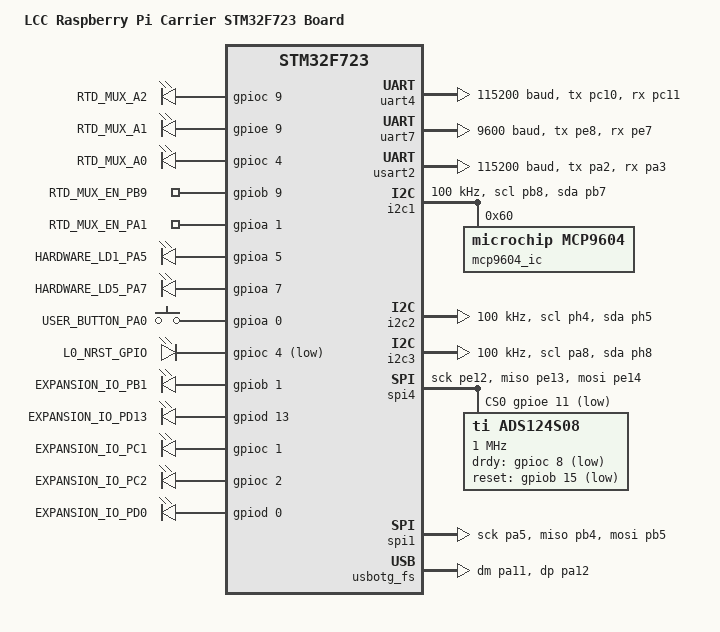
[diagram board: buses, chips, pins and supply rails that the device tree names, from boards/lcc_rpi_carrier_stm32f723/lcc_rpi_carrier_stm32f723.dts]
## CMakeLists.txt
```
cmake_minimum_required(VERSION 3.20.0)
set(BOARD_ROOT ${CMAKE_CURRENT_SOURCE_DIR})
find_package(Zephyr REQUIRED HINTS $ENV{ZEPHYR_BASE})
project(stm32f723_app)

# ==========================================
# Force CMake Re-run
# ==========================================
# 1. Automate .c files (Sources)
# ==========================================
file(GLOB_RECURSE APP_SOURCES 
    "src/*.c"
    "drivers/*.c"
)
target_sources(app PRIVATE ${APP_SOURCES})
# ==========================================
# 2. Automate .h files (Include Directories)
# ==========================================
file(GLOB_RECURSE APP_HEADERS 
    "src/*.h"
    "drivers/*.h"
)
# Extract just the folder path from each header file
set(APP_INCLUDE_DIRS "")
foreach(HEADER_FILE ${APP_HEADERS})
    get_filename_component(HEADER_DIR ${HEADER_FILE} DIRECTORY)
    list(APPEND APP_INCLUDE_DIRS ${HEADER_DIR})
endforeach()
# Remove duplicate folders from the list
list(REMOVE_DUPLICATES APP_INCLUDE_DIRS)
# Give the list of folders to the compiler
target_include_directories(app PRIVATE ${APP_INCLUDE_DIRS})

target_include_directories(app PRIVATE ${ZEPHYR_BASE}/drivers/adc)
```

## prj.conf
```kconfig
# ==========================================
# Core Kernel & System Configuration
# ==========================================
CONFIG_NEWLIB_LIBC=y
CONFIG_HEAP_MEM_POOL_SIZE=2048
CONFIG_CBPRINTF_FP_SUPPORT=y

# ==========================================
# Hardware Busses (I2C, SPI, GPIO)
# ==========================================
CONFIG_GPIO=y
CONFIG_I2C=y
CONFIG_I2C_STM32=y
CONFIG_SPI=y

# ==========================================
# Drivers (Sensors & ADCs)
# ==========================================
CONFIG_SENSOR=y
CONFIG_MCP9600=y
CONFIG_ADC=y
CONFIG_ADC_INIT_PRIORITY=80

# Keep upstream driver disabled, custom driver available
CONFIG_ADC_ADS1X4S0X=n
# Re-enable the structure fields needed by ADS124S08:
# CONFIG_ADC_CONFIGURABLE_INPUTS=y
# CONFIG_ADC_CONFIGURABLE_EXCITATION_CURRENT_SOURCE_PIN=y
# CONFIG_ADC_CONFIGURABLE_VBIAS_PIN=y

# ==========================================
# DMA & UART (Display Protocol)
# ==========================================
CONFIG_SERIAL=y
CONFIG_UART_ASYNC_API=y
CONFIG_DMA=y
CONFIG_NOCACHE_MEMORY=y

# Disable standard UART features to prevent conflicts with DMA
CONFIG_UART_CONSOLE=n
CONFIG_UART_INTERRUPT_DRIVEN=n

# Optional DMA debug
CONFIG_DMA_LOG_LEVEL_DBG=y

# ==========================================
# Logging & Console (SEGGER RTT)
# ==========================================
CONFIG_LOG=y
CONFIG_PRINTK=y
CONFIG_LOG_DEFAULT_LEVEL=3
CONFIG_LOG_RUNTIME_FILTERING=y
CONFIG_ASSERT=y

# Use RTT instead of UART for logs
CONFIG_USE_SEGGER_RTT=y
CONFIG_LOG_BACKEND_RTT=y
CONFIG_RTT_CONSOLE=y
CONFIG_LOG_BACKEND_UART=n
CONFIG_CONSOLE=n
CONFIG_STDOUT_CONSOLE=n

# RTT Buffers & Threading safety
CONFIG_SEGGER_RTT_BUFFER_SIZE_UP=4096
CONFIG_SEGGER_RTT_BUFFER_SIZE_DOWN=16
CONFIG_LOG_MODE_IMMEDIATE=y
# ==========================================
# Threading & Memory Protection
# ==========================================
CONFIG_NUM_PREEMPT_PRIORITIES=15
CONFIG_MAIN_STACK_SIZE=16384
CONFIG_SMF=y

# MPU & Stack Guard Rails
CONFIG_MPU=y
CONFIG_ARM_MPU=y
CONFIG_HW_STACK_PROTECTION=y
CONFIG_STACK_SENTINEL=y
CONFIG_INIT_STACKS=y

CONFIG_THREAD_STACK_INFO=y

# ==========================================
# Hardware Floating Point Unit (FPU)
# ==========================================
CONFIG_FPU=y
CONFIG_FPU_SHARING=y
CONFIG_SYSTEM_WORKQUEUE_STACK_SIZE=2048

# ==========================================
# Debug optimization
# ==========================================
CONFIG_DEBUG_OPTIMIZATIONS=y

# ==========================================
# Scheduler analysis
# ==========================================
CONFIG_THREAD_MONITOR=y
CONFIG_THREAD_NAME=y
CONFIG_THREAD_RUNTIME_STATS=y
CONFIG_THREAD_ANALYZER=y
CONFIG_THREAD_ANALYZER_AUTO=y
CONFIG_THREAD_ANALYZER_AUTO_INTERVAL=5
```

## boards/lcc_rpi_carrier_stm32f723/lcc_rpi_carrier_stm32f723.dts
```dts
/*
 * SPDX-License-Identifier: Apache-2.0
 * * Custom Board Devicetree for LCC Raspberry Pi Carrier STM32F723 Board
 * Structured for scalability, easy maintenance, and explicit GPIO naming.
 */

/dts-v1/;

#include <st/f7/stm32f7.dtsi>
#include <st/f7/stm32f723Xe.dtsi>
#include <st/f7/stm32f723i(c-e)kx-pinctrl.dtsi>// zephyr->modules->hal->stm32->dts
#include <zephyr/dt-bindings/sensor/mcp9600.h>

//#include <zephyr/dt-bindings/pinctrl/stm32-pinctrl.h>

#include <zephyr/dt-bindings/input/input-event-codes.h>
/ {
    model = "LCC Raspberry Pi Carrier STM32F723 Board";
    compatible = "lcc,lcc_rpi_carrier_stm32f723";

    chosen {
        // zephyr,console = &usart6;
        // zephyr,shell-uart = &usart6;
        zephyr,sram = &sram0;
        zephyr,flash = &flash0;
        // zephyr,flash-controller = &mx25r512;
    };

    /* * =========================================================================
     * GPIO CONFIGURATIONS (LEDS, BUTTONS, & GENERAL PURPOSE IO)
     * =========================================================================
     */
    rtd_mux: rtd_mux {
        compatible = "gpio-leds";

        mux_addr2: mux_a2 {
            gpios = <&gpioc 9 GPIO_ACTIVE_HIGH>;
            label = "RTD_MUX_A2";
        };
        mux_addr1: mux_a1 {
            gpios = <&gpioe 9 GPIO_ACTIVE_HIGH>;
            label = "RTD_MUX_A1";
        };
        mux_addr0: mux_a0 {
            gpios = <&gpioc 4 GPIO_ACTIVE_HIGH>;
            label = "RTD_MUX_A0";
        };

        /*Complementary MUX Enable / Select Pins */
        mux_en1_b9: mux_en1_b9 {
            gpios = <&gpiob 9 GPIO_ACTIVE_HIGH>;
            label = "RTD_MUX_EN_PB9";
        };
        mux_en2_a1: mux_en2_a1 {
            gpios = <&gpioa 1 GPIO_ACTIVE_HIGH>;
            label = "RTD_MUX_EN_PA1";
        };

    };
    
    /* Standard LED Nodes */
    leds {
        compatible = "gpio-leds";

        gpio_pa5: led_pa5 {
            gpios = <&gpioa 5 GPIO_ACTIVE_HIGH>;
            label = "HARDWARE_LD1_PA5";
        };

        gpio_pa7: led_pa7 {
            gpios = <&gpioa 7 GPIO_ACTIVE_HIGH>;
            label = "HARDWARE_LD5_PA7";
        };

        // gpio_pb1: led_pb1 {
        //     gpios = <&gpiob 1 GPIO_ACTIVE_HIGH>;
        //     label = "HARDWARE_LD6_PB1";
        // };
    };

    /* Input Keys / Interrupt-driven Buttons */
    gpio_keys {
        compatible = "gpio-keys";

        gpio_pa0: button_pa0 {
            gpios = <&gpioa 0 GPIO_ACTIVE_HIGH>;
            label = "USER_BUTTON_PA0";
            zephyr,code = <INPUT_KEY_0>;
        };
    };

    /* * SCALABLE GPIO EXPANSION:
     * Use this block to map miscellaneous digital inputs/outputs on your board.
     * Binding to "gpio-leds" lets you manipulate them easily in C code using:
     * gpio_pin_configure_dt() / gpio_pin_set_dt()
     */
    custom_gpios {
        compatible = "gpio-leds";

        /* Template: Duplicate and modify these blocks as your board needs grow */

        l0_reset_pin: l0_reset_pin {
            gpios = <&gpioc 4 GPIO_ACTIVE_LOW>;
            label = "L0_NRST_GPIO";
        };

		gpio_pb1: io_pb1 {
            gpios = <&gpiob 1 GPIO_ACTIVE_HIGH>;
            label = "EXPANSION_IO_PB1";
        };

		gpio_pd13: io_pd13 {
            gpios = <&gpiod 13 GPIO_ACTIVE_HIGH>;
            label = "EXPANSION_IO_PD13";
        };

        gpio_pc1: io_pc1 {
            gpios = <&gpioc 1 GPIO_ACTIVE_HIGH>;
            label = "EXPANSION_IO_PC1";
        };

        gpio_pc2: io_pc2 {
            gpios = <&gpioc 2 GPIO_ACTIVE_HIGH>;
            label = "EXPANSION_IO_PC2";
        };

        gpio_pd0: io_pd0 {
            gpios = <&gpiod 0 GPIO_ACTIVE_HIGH>;
            label = "EXPANSION_IO_PD0";
        };
    };

  
    /* Application-friendly aliases for your main application logic loop */
    aliases {
        l0-reset = &l0_reset_pin;
        led0 = &gpio_pa5;
        led1 = &gpio_pa7;
        // led2 = &gpio_pb1;
        sw0  = &gpio_pa0;
        /* Custom io aliases can be mapped here as well (e.g., test-point = &gpio_pc1;) */
        /* ADD THESE TWO LINES FOR YOUR TASKS */
        vacuum-gpio = &gpio_pd13;    /* Points to io_pd13 (Pin D13) */
        collector-gpio = &gpio_pb1; /* Points to io_pb1 (Pin B1) */
        mux-a0 = &mux_addr0;
        mux-a1 = &mux_addr1;
        mux-a2 = &mux_addr2;

         /* Aliases for PB9 and PA1 */
        mux-en1 = &mux_en1_b9;
        mux-en2 = &mux_en2_a1;

    };
};

/* * =========================================================================
 * CLOCK & SYSTEM SYSTEM CONFIGURATION
 * =========================================================================
 */

&clk_hse {
    clock-frequency = <DT_FREQ_M(25)>;
    status = "disabled"; /* Change to "okay" if utilizing an external crystal oscillator */
};

&clk_hsi {
    status = "okay";
};

&pll {
    div-m = <8>;
    mul-n = <216>;
    div-p = <2>;
    div-q = <9>;
    clocks = <&clk_hsi>;
    status = "okay";
};

&rcc {
    clocks = <&pll>;
    clock-frequency = <DT_FREQ_M(216)>;
    ahb-prescaler = <1>;
    apb1-prescaler = <4>;
    apb2-prescaler = <2>;
};

/* * =========================================================================
 * COMMUNICATION PROTOCOLS (UARTS, I2C, SPI)
 * =========================================================================
 */

/* =========================================================================
 * UART4 + DMA ::::::::::::Accessory IOB:::::::
 * ========================================================================= */

&uart4 {
    /* PC10 is TX, PC11 is RX using alternative function mappings */
    pinctrl-0 = <&uart4_tx_pc10 &uart4_rx_pc11>;
    pinctrl-names = "default";
    current-speed = <115200>; /* Adjust to match accessory IOB */
    status = "okay";

    /* DMA mapping for STM32F7 UART4 */
    dmas = <&dma1 4 4 (STM32_DMA_PERIPH_TX | STM32_DMA_PRIORITY_HIGH) 0>,  /* Stream 4, Channel 4 (TX) */
           <&dma1 2 4 (STM32_DMA_PERIPH_RX | STM32_DMA_PRIORITY_HIGH) 0>;  /* Stream 2, Channel 4 (RX) */
    
    dma-names = "tx", "rx";
};

/* =========================================================================
 * CUSTOM TERMINAL DISPLAY CONFIGURATION (UART7 + DMA1)
 * ========================================================================= */

&uart7 {
    /* PE7 is RX, PE8 is TX using alternative function mappings */
    pinctrl-0 = <&uart7_tx_pe8 &uart7_rx_pe7>;
    pinctrl-names = "default";
    current-speed = <9600>;
    status = "okay";

    /* FIXED: Raw hex values explicitly resolve the parsing shift */
    dmas = <&dma1 1 5 (STM32_DMA_PERIPH_TX | STM32_DMA_PRIORITY_HIGH) 0>,  /* Stream 1, Channel 5 (TX Channel) */
           <&dma1 3 5 (STM32_DMA_PERIPH_RX | STM32_DMA_PRIORITY_HIGH) 0>;  /* Stream 3, Channel 5 (RX Channel) */

    //single-wire;       
    dma-names = "tx", "rx";
};

&dma1 {
    status = "okay";
};

/* Auxiliary Communication Channel / Modbus / External Peripherals */
&usart2 {
    pinctrl-0 = <&usart2_tx_pa2 &usart2_rx_pa3>;
    pinctrl-names = "default";
    current-speed = <115200>;
    status = "okay";
};

/* I2C Bus 1 - e.g., Onboard EEPROM or Sensors */

/* I2C Bus 1 - Dedicated to MCP9604 Thermocouple Converter */
&i2c1 {
    pinctrl-0 = <&i2c1_scl_pb8 &i2c1_sda_pb7>; 
    pinctrl-names = "default";
    clock-frequency = <I2C_BITRATE_STANDARD>; 
    status = "okay";

    /* Declare the single physical chip address */
    mcp9604_ic: mcp9604@60 {
        compatible = "microchip,mcp9604";
        reg = <0x60>;
        status = "okay";
    };
};

/* I2C Bus 2 - e.g., Display or Real-Time Clock */
&i2c2 {
    pinctrl-0 = <&i2c2_scl_ph4 &i2c2_sda_ph5>;
    pinctrl-names = "default";
    clock-frequency = <I2C_BITRATE_STANDARD>;
    status = "okay";
};

/* I2C Bus 3 - Expansion Header */
&i2c3 {
    pinctrl-0 = <&i2c3_scl_pa8 &i2c3_sda_ph8>;
    pinctrl-names = "default";
    clock-frequency = <I2C_BITRATE_STANDARD>;
    status = "okay";
};

&spi4 {
    pinctrl-0 = <&spi4_sck_pe12 &spi4_miso_pe13 &spi4_mosi_pe14>;
    pinctrl-names = "default";
    status = "okay";
    
    /* Define the CS pin here for the bus controller */
    cs-gpios = <&gpioe 11 GPIO_ACTIVE_LOW>;
            //    <&gpioe 9 GPIO_ACTIVE_LOW>;
    

    /* Existing ADS124S08 using CS index 0 */
    ads124s08@0 {
        compatible = "ti,ads124s08";
        reg = <0>; /* Maps to cs-gpios index 0 */
        spi-max-frequency = <1000000>;
        spi-cpha; 
        #io-channel-cells = <1>;
        #address-cells = <1>;
        #size-cells = <0>;

        idac-current = <500>;
        drdy-gpios = <&gpioc 8 GPIO_ACTIVE_LOW>; 
        reset-gpios = <&gpiob 15 GPIO_ACTIVE_LOW>;

        channel@0 {
            reg = <0>;
            zephyr,gain = "ADC_GAIN_1";
            zephyr,reference = "ADC_REF_INTERNAL";
            zephyr,acquisition-time = <ADC_ACQ_TIME_DEFAULT>;
            zephyr,input-positive = <1>; 
            zephyr,input-negative = <0>;
        };
    };

    // ltc2983: ltc2983@1 {
    //     compatible = "adi,ltc2983";
    //     reg = <1>;

    //     spi-max-frequency = <1000000>;

    //     spi-cpha;

    //     duplex = <0>;
    //     frame-format = <0>;
    //     spi-interframe-delay-ns = <0>;

    //     status = "okay";
    // };

};

/* SPI Bus 1 - High-speed peripheral bus */
&spi1 {
    pinctrl-0 = <&spi1_sck_pa5 &spi1_miso_pb4 &spi1_mosi_pb5>;
    pinctrl-names = "default";
    status = "okay";
    
    /* * Define custom GPIO Chip Selects here to use Zephyr's automated CS management.
     * Example: cs-gpios = <&gpioa 4 GPIO_ACTIVE_LOW>;
     */
};

/* * =========================================================================
 * EXTERNAL STORAGE & HIGH-SPEED FLASH (QSPI)
 * =========================================================================
 */
// &quadspi {
//     pinctrl-names = "default";
//     pinctrl-0 = <&quadspi_clk_pb2    &quadspi_bk1_ncs_pb6
//                  &quadspi_bk1_io0_pc9 &quadspi_bk1_io1_pc10
//                  &quadspi_bk1_io2_pe2 &quadspi_bk1_io3_pd13>;
//     flash-id = <1>;
//     status = "okay";

//     mx25r512: qspi-nor-flash@0 {
//         compatible = "st,stm32-qspi-nor";
//         reg = <0>;
//         size = <DT_SIZE_M(512)>; /* 512 Mbits (64 Megabytes) */
//         qspi-max-frequency = <8000000>;
//         cs-high-time = <3>; /* >= 30 ns */
//         spi-bus-width = <4>;
//         writeoc = "PP_1_4_4";
//         status = "okay";
//     };
// };

/* * =========================================================================
 * USB DEVICE CONFIGURATION
 * =========================================================================
 */
zephyr_udc0: &usbotg_fs {
    pinctrl-0 = <&usb_otg_fs_dm_pa11 &usb_otg_fs_dp_pa12>;
    pinctrl-names = "default";
    status = "okay";
};
```

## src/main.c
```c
#include <zephyr/kernel.h>
#include <zephyr/logging/log.h>
#include "boot_sequence.h"
#include "task_manager.h"

LOG_MODULE_REGISTER(main_app, LOG_LEVEL_INF);

int main(void)
{
    system_boot_sequence();

    while (1) 
    {
        k_msleep(5000);
        reset_timeline_trace();
        LOG_INF("Main ENTERED");
    }

    return 0;
}
```

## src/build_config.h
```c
#ifndef BUILD_CONFIG_H
#define BUILD_CONFIG_H

/* ======================================================== */
/*  SIMULATION SWITCH                                 */
/* Comment out this line to return to physical hardware!    */
/* ======================================================== */
#define SIMULATION 1
#ifdef SIMULATION
    /* 1 = Simulate TRIAD (Tilt Valve Present = true,  Vent Valve Present = true)
     * 0 = Simulate FD    (Tilt Valve Present = false, Vent Valve Present = true)
     */
    #define SIMULATE_AS_TRIAD   1
#endif

#endif /* BUILD_CONFIG_H */
```

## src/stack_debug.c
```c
#include <zephyr/kernel.h>
#include <zephyr/logging/log.h>

LOG_MODULE_REGISTER(stack_test);

void print_stack_usage(void)
{
    size_t unused;

    int ret = k_thread_stack_space_get(k_current_get(), &unused);

    if (ret == 0) 
    {
    //    //LOG_INF("Thread %s unused stack: %u bytes",
    //             k_thread_name_get(k_current_get()),
    //             unused);
    }
}
```

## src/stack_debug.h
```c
#ifndef STACK_DEBUG_H
#define STACK_DEBUG_H

void print_stack_usage(void);

#endif
```

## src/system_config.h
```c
#ifndef SYSTEM_CONFIG_H
#define SYSTEM_CONFIG_H

/* ======================================================== */
/* MASTER SIMULATION SWITCH                                 */
/* Comment out this line to return to physical hardware!    */
/* ======================================================== */
#define SIMULATION 1

#endif /* SYSTEM_CONFIG_H */
```

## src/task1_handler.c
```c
/*
 * Copyright (c) 2026 Labconco Corporation
 * SPDX-License-Identifier: Apache-2.0
 */

#include <zephyr/logging/log.h>
#include "platform/platform_gpio.h"
#include "stack_debug.h"
LOG_MODULE_REGISTER(task1, LOG_LEVEL_INF);

int task1_init(void)
{
    print_stack_usage();
    if (!platform_gpio_is_ready(PLATFORM_GPIO_VACUUM_PD13)) {
        return -1;
    }
    return platform_gpio_config_output_inactive(PLATFORM_GPIO_VACUUM_PD13);
}

void task1_vacuum_controller(void)
{
    platform_gpio_toggle(PLATFORM_GPIO_VACUUM_PD13);
    //LOG_INF("[Task1] Entered");
}
```

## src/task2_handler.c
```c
/*
 * Copyright (c) 2026 Labconco Corporation
 * SPDX-License-Identifier: Apache-2.0
 */

#include <zephyr/logging/log.h>
#include "platform/platform_gpio.h"
#include "stack_debug.h"
LOG_MODULE_REGISTER(task2, LOG_LEVEL_INF);

int task2_init(void)
{
    print_stack_usage();
    if (!platform_gpio_is_ready(PLATFORM_GPIO_COLLECTOR_PB1)) {
        return -1;
    }
    return platform_gpio_config_output_inactive(PLATFORM_GPIO_COLLECTOR_PB1);
}

void task2_collector_controller(void)
{
    platform_gpio_toggle(PLATFORM_GPIO_COLLECTOR_PB1);
    //LOG_INF("[Task2] Entered");;
}
```

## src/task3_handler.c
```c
/*
 * Copyright (c) 2026 Labconco Corporation
 * SPDX-License-Identifier: Apache-2.0
 */

#include <zephyr/kernel.h>
#include <zephyr/smf.h>
#include <zephyr/logging/log.h>
#include "task3_handler.h"
#include "stack_debug.h"
LOG_MODULE_REGISTER(task3, LOG_LEVEL_INF);

struct counter_object {
   struct smf_ctx ctx;
   /* All User Defined Data Follows */
   int counter;
};

/*------------------------------------------------------------------
 * State IDs
 *----------------------------------------------------------------*/
enum counter_states {
    COUNT_UP,
    COUNT_DOWN,
};

static struct counter_object counter_obj;

static const struct smf_state states[];

/*-----------------------------
 * COUNT_UP State
 *----------------------------*/
static void count_up_entry(void *obj)
{
    printk("\nEntering COUNT_UP\n");
}

static enum smf_state_result count_up_run(void *obj)
{
    struct counter_object *s = obj;

    //printk("COUNT_UP: %d\n", s->counter);

    if (s->counter >= 5) {
        smf_set_state(SMF_CTX(s), &states[COUNT_DOWN]);
        return SMF_EVENT_HANDLED;
    }

    s->counter++;
    return SMF_EVENT_PROPAGATE;
}

/*-----------------------------
 * COUNT_DOWN State
 *----------------------------*/
static void count_down_entry(void *obj)
{
    //printk("\nEntering COUNT_DOWN\n");
}

static enum smf_state_result count_down_run(void *obj)
{
    struct counter_object *s = obj;

    //printk("COUNT_DOWN: %d\n", s->counter);

    if (s->counter <= 0) {
        smf_set_state(SMF_CTX(s), &states[COUNT_UP]);
        return SMF_EVENT_HANDLED;
    }

    s->counter--;
    return SMF_EVENT_PROPAGATE;
}

/*-----------------------------
 * State Table
 *----------------------------*/
static const struct smf_state states[] = {
    [COUNT_UP] = SMF_CREATE_STATE(
        count_up_entry,
        count_up_run,
        NULL,
        NULL,
        NULL),

    [COUNT_DOWN] = SMF_CREATE_STATE(
        count_down_entry,
        count_down_run,
        NULL,
        NULL,
        NULL),
};

void counter_smf_init(void)
{
    counter_obj.counter = 0;

    smf_set_initial(
        SMF_CTX(&counter_obj),
        &states[COUNT_UP]);
}

void counter_smf_run(void)
{
    smf_run_state(SMF_CTX(&counter_obj));
}

void task3_smf(void)
{
    counter_smf_run();
}

int task3_init(void)
{
    print_stack_usage();
    counter_smf_init();
    return 0;
}
```

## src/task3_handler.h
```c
#ifndef TASK3_HANDLER_H_
#define TASK3_HANDLER_H_

int task3_init(void);
void task3_smf(void);

#endif /* TASK3_HANDLER_H_ */
```

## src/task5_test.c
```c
/*
 * Copyright (c) 2026 Labconco Corporation
 * SPDX-License-Identifier: Apache-2.0
 */

#include <zephyr/logging/log.h>
#include "platform/platform_gpio.h"
#include "stack_debug.h"
#include <zephyr/logging/log.h>
LOG_MODULE_REGISTER(task5, LOG_LEVEL_INF);

int task5_init(void)
{
    print_stack_usage();
    // if (!platform_gpio_is_ready(PLATFORM_GPIO_VACUUM_PD13)) {
    //     return -1;
    // }
    // return platform_gpio_config_output_inactive(PLATFORM_GPIO_VACUUM_PD13);
    return 0;
}

void task5_vacuum_controller(void)
{
    // platform_gpio_toggle(PLATFORM_GPIO_VACUUM_PD13);
    //LOG_INF("[Task5] Entered");
}
```

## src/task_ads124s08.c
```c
#include "build_config.h"
#include <zephyr/kernel.h>
#include <zephyr/drivers/adc.h>
#include <zephyr/logging/log.h>
#include "task_ads124s08.h"
#include <math.h>
#include <zephyr/drivers/gpio.h>
#include "DataStorage/main_iob_data.h"
#include "communication/protocol_defs.h"

LOG_MODULE_REGISTER(task_ads, LOG_LEVEL_INF);

/* RTD constants */
#define VREF            2.5f
#define IDAC_CURRENT    0.000500f
#define ADC_FS          8388608.0f

#define RREF        2058.0f

/* PT1000 Callendar-Van Dusen coefficients */
#define RTD_R0          1000.0f
#define RTD_A           3.9083e-3f
#define RTD_B          -5.775e-7f

#define ADS_AINCOM       12  /* Zephyr internal index for AINCOM */

#define MUX_NODE DT_PATH(rtd_mux)

static const struct gpio_dt_spec mux_a0 = GPIO_DT_SPEC_GET(DT_ALIAS(mux_a0), gpios);//PC4
static const struct gpio_dt_spec mux_a1 = GPIO_DT_SPEC_GET(DT_ALIAS(mux_a1), gpios);//PE9
static const struct gpio_dt_spec mux_a2 = GPIO_DT_SPEC_GET(DT_ALIAS(mux_a2), gpios);//PC9
static const struct gpio_dt_spec mux_en1 = GPIO_DT_SPEC_GET(DT_ALIAS(mux_en1), gpios);//PB9
static const struct gpio_dt_spec mux_en2 = GPIO_DT_SPEC_GET(DT_ALIAS(mux_en2), gpios);//PA1

/* Helper to drive address lines 000 to 111 */
static void set_rtd_mux_channel(uint8_t address)
{

    gpio_pin_set_dt(&mux_en1, 0);
    gpio_pin_set_dt(&mux_en2, 0);

    /* Change MUX address */
    gpio_pin_set_dt(&mux_a0, (address >> 0) & 1);
    gpio_pin_set_dt(&mux_a1, (address >> 1) & 1);
    gpio_pin_set_dt(&mux_a2, (address >> 2) & 1);

    if (address < 8) 
    {
        gpio_pin_set_dt(&mux_en1, 1);
    } 
    else 
    {
        gpio_pin_set_dt(&mux_en2, 1);
    }

    /* Initial analog settling delay */
    k_msleep(10);
}

/* ========================================================
 * PRODUCT-SPECIFIC RTD CONFIGURATIONS
 * ======================================================== */
struct rtd_config 
{
    uint8_t channel_id;
    uint8_t input_positive; // ADS124S08 sense pin (AIN3 to AIN10)
    uint8_t input_negative; // ADS_AINCOM (12)
    uint8_t idac_pin;        // ALWAYS 11 (Excitation routes out AIN11)
    uint8_t mux_channel;    // 0 to 7 (Address for PC9, PE9, PC4)
    uint8_t action_id;
};
/* 1a. Freeze Dry (With Mini Chamber) */
static const struct rtd_config fd_mini_chamber_configs[] = 
{
    { .channel_id = 0, .input_positive = 1, .input_negative = 0, .idac_pin = 5, .action_id = SENSOR_COLLECTOR_TEMP },
    { .channel_id = 1, .input_positive = 3, .input_negative = 2, .idac_pin = 5, .action_id = SENSOR_MINI_CHAMBER_TEMP }
};
/* 1b. Freeze Dry (With Shell Freezer) */
static const struct rtd_config fd_shell_configs[] = 
{
    { .channel_id = 0, .input_positive = 1, .input_negative = 0, .idac_pin = 5, .action_id = SENSOR_COLLECTOR_TEMP },
    { .channel_id = 1, .input_positive = 3, .input_negative = 2, .idac_pin = 5, .action_id = SENSOR_SHELL_FREEZER_TEMP_SENSOR }
};

/* 2. Triad (4 RTDs) */
static const struct rtd_config triad_configs[] = 
{
    { .channel_id = 0, .input_positive = 1, .input_negative = 0, .idac_pin = 5, .action_id = SENSOR_COLLECTOR_TEMP},
    { .channel_id = 1, .input_positive = 3, .input_negative = 2, .idac_pin = 5, .action_id = SENSOR_SHELF1_TEMP }, 
    { .channel_id = 2, .input_positive = 4, .input_negative = 6, .idac_pin = 5, .action_id = SENSOR_SAMPLE1_TEMP },
    { .channel_id = 3, .input_positive = 7, .input_negative = 8, .idac_pin = 5, .action_id = SENSOR_LEXSOL_TEMP}
};

/* 3. Max Config (11 RTDs) */

static const struct rtd_config max_configs[] = 
{
    /* MUX 000 -> Sensor 1 on AIN3 */
    { .channel_id = 0, .input_positive = 3,  .input_negative = ADS_AINCOM, .idac_pin = 11, .mux_channel = 0, .action_id = SENSOR_RTD_TEMP1 },
    /* MUX 001 -> Sensor 2 on AIN4 */
    { .channel_id = 0, .input_positive = 4,  .input_negative = ADS_AINCOM, .idac_pin = 11, .mux_channel = 1, .action_id = SENSOR_RTD_TEMP2 },
    /* MUX 010 -> Sensor 3 on AIN5 */
    { .channel_id = 0, .input_positive = 5,  .input_negative = ADS_AINCOM, .idac_pin = 11, .mux_channel = 2, .action_id = SENSOR_RTD_TEMP3 },
    /* MUX 011 -> Sensor 4 on AIN6 */
    { .channel_id = 0, .input_positive = 6,  .input_negative = ADS_AINCOM, .idac_pin = 11, .mux_channel = 3, .action_id = SENSOR_RTD_TEMP4 },
    /* MUX 100 -> Sensor 5 on AIN7 */
    { .channel_id = 0, .input_positive = 7,  .input_negative = ADS_AINCOM, .idac_pin = 11, .mux_channel = 4, .action_id = SENSOR_RTD_TEMP5 },
    /* MUX 101 -> Sensor 6 on AIN8 */
    { .channel_id = 0, .input_positive = 8,  .input_negative = ADS_AINCOM, .idac_pin = 11, .mux_channel = 5, .action_id = SENSOR_RTD_TEMP6 },
    /* MUX 110 -> Sensor 7 on AIN9 */
    { .channel_id = 0, .input_positive = 9,  .input_negative = ADS_AINCOM, .idac_pin = 11, .mux_channel = 6, .action_id = SENSOR_RTD_TEMP7 },
    /* MUX 111 -> Sensor 8 on AIN10 */
    { .channel_id = 0, .input_positive = 10, .input_negative = ADS_AINCOM, .idac_pin = 11, .mux_channel = 7, .action_id = SENSOR_RTD_TEMP8 },

    /* --- MUX 2 (AIN0, AIN1, AIN2) --- */
    /* MUX 000 on MUX2 -> Sensor 9 on AIN0 */
    { .channel_id = 0, .input_positive = 0,  .input_negative = ADS_AINCOM, .idac_pin = 11, .mux_channel = 8,  .action_id = SENSOR_RTD_TEMP9 },
    /* MUX 001 on MUX2 -> Sensor 10 on AIN1 */
    { .channel_id = 0, .input_positive = 1,  .input_negative = ADS_AINCOM, .idac_pin = 11, .mux_channel = 9,  .action_id = SENSOR_RTD_TEMP10 },
    /* MUX 010 on MUX2 -> Sensor 11 on AIN2 */
    { .channel_id = 0, .input_positive = 2,  .input_negative = ADS_AINCOM, .idac_pin = 11, .mux_channel = 10, .action_id = SENSOR_RTD_TEMP11 },
};

/* --- DYNAMIC POINTERS --- */
static const struct rtd_config *active_rtds = NULL;
static uint8_t num_active_rtds = 0;

const struct device *ads_dev = DEVICE_DT_GET_ANY(ti_ads124s08);

/* Helper function to chop an int16_t into 2 bytes and send it to memory */
static void save_temp_to_memory(uint8_t action_id, int16_t temp_value)
{
    uint8_t raw_data[2];
    
    // Convert 16-bit integer into a 2-byte array (Little Endian)
    raw_data[0] = temp_value & 0xFF;         // LSB
    raw_data[1] = (temp_value >> 8) & 0xFF;  // MSB
    
    UpdateMainIOBData(action_id, raw_data);
}

/*
 * Convert ADC code to RTD resistance
 */
static float adc_to_resistance(int32_t adc)
{
     return ((float)adc / ADC_FS) * RREF;
}

/*
 * Convert PT1000 resistance to temperature
 *
 * Valid for temperature > 0C
 */
static float resistance_to_temperature(float resistance)
{
    float temp;

    temp = (-RTD_A +    sqrtf(     RTD_A * RTD_A -    4 * RTD_B *     (1 - resistance / RTD_R0)  ))   /      (2 * RTD_B);

    return temp;
}

int ads_task_init(void) 
{
    
    /* to be configured based on product type */
    active_rtds = max_configs;
    num_active_rtds = ARRAY_SIZE(max_configs);
    
    /* Configure PC9, PE9, PC4 as outputs set to 0 */
    gpio_pin_configure_dt(&mux_a0, GPIO_OUTPUT_INACTIVE);
    gpio_pin_configure_dt(&mux_a1, GPIO_OUTPUT_INACTIVE);
    gpio_pin_configure_dt(&mux_a2, GPIO_OUTPUT_INACTIVE);

    /* Configure PB9 and PA1 as outputs (initially PB9=0, PA1=1) */
    gpio_pin_configure_dt(&mux_en1, GPIO_OUTPUT_INACTIVE);
    gpio_pin_configure_dt(&mux_en2, GPIO_OUTPUT_ACTIVE);

#ifndef SIMULATION
    if (!device_is_ready(ads_dev)) 
    {
        LOG_ERR("ADS124S08 not ready");
        return -ENODEV;
    }
    LOG_INF("ADS124S08 device ready");
#endif
    return 0;

}

void ads_task_run(void)
{

#ifdef SIMULATION
    /* --- SIMULATION CODE --- */
    static int16_t fake_collector = 200;  // 20.0 °C
    static int16_t fake_shelf     = 100;  // 10.0 °C
    
    fake_collector += 5;                 
    fake_shelf     += 2;     
    if (fake_collector > 800) fake_collector = -200;           
    if (fake_shelf > 400) fake_shelf = 0;
    // Safely inject our fake data
    save_temp_to_memory(SENSOR_COLLECTOR_TEMP, fake_collector);
    save_temp_to_memory(SENSOR_SHELL_DRY_LEXSOL, fake_collector - 50);
    save_temp_to_memory(SENSOR_SHELF1_TEMP, fake_shelf);
    save_temp_to_memory(SENSOR_SAMPLE1_TEMP, fake_shelf + 10);

#else
    /* --- HARDWARE CODE --- */

    #define NUM_SAMPLES 5

    int err;
    int32_t adc_samples[NUM_SAMPLES];

    /* Read all RTDs sequentially */
    for (int i = 0; i < num_active_rtds; i++)
    {
        /* 1. Select RTD using external MUX */
        set_rtd_mux_channel(active_rtds[i].mux_channel);

        /* Allow MUX and analog circuit to settle */
        k_msleep(100);

        /* 2. Configure ADS124S08 */
        struct adc_channel_cfg cfg = 
        {
            .channel_id = 0,
            .differential = true,
            .input_positive = active_rtds[i].input_positive,
            .input_negative = active_rtds[i].input_negative,
            .gain = ADC_GAIN_1,
            .reference =ADC_REF_EXTERNAL0 , // ADC_REF_INTERNAL
            .acquisition_time = ADC_ACQ_TIME_DEFAULT,
            .current_source_pin_set = true,
            .current_source_pin = { 11, 15 }
        };

        err = adc_channel_setup(ads_dev, &cfg);
        
        k_msleep(100);

        if (err != 0)
        {
            LOG_ERR("ADC setup failed for RTD%d: %d", i + 1, err);
            continue;
        }

        /* 3. Configure ADC sequence */
        struct adc_sequence sequence = {
            .channels = BIT(0),
            .buffer = &adc_samples[0],
            .buffer_size = sizeof(adc_samples[0]),
            .resolution = 24,
            .oversampling = 0,
            .calibrate = false,
        };

        float resistance_sum = 0.0f;
        float temperature_sum = 0.0f;
        int32_t adc_sum = 0;

        printk("\n========== RTD%d (AIN%d) ==========\n",
               i + 1,
               active_rtds[i].input_positive);

        /* 4. Take 5 readings */
        for (int sample = 0; sample < NUM_SAMPLES; sample++)
        {
            sequence.buffer = &adc_samples[sample];

            err = adc_read(ads_dev, &sequence);

            if (err != 0)
            {
                LOG_ERR("ADC read failed RTD%d Sample%d: %d",
                        i + 1, sample + 1, err);
                continue;
            }

            int32_t adc_value = adc_samples[sample];

            float resistance = adc_to_resistance(adc_value);
            float temperature = resistance_to_temperature(resistance);

            adc_sum += adc_value;
            resistance_sum += resistance;
            temperature_sum += temperature;

            /* Print every individual reading */
            printk("RTD%d | Sample %d | ADC=%ld | R=%.3f Ohm | Temp=%.3f C\n",
                   i + 1,
                   sample + 1,
                   (long)adc_value,
                   (double)resistance,
                   (double)temperature);

            k_msleep(20);
        }

        /* 5. Calculate averages */
        float avg_adc = (float)adc_sum / NUM_SAMPLES;
        float avg_resistance = resistance_sum / NUM_SAMPLES;
        float avg_temperature = temperature_sum / NUM_SAMPLES;

        printk("------------------------------------\n");

        printk("RTD%d AVERAGE OF 5 SAMPLES:\n", i + 1);

        printk("Average ADC Code : %.2f\n", (double)avg_adc);
        printk("Average Resistance: %.3f Ohm\n", (double)avg_resistance);
        printk("Average Temperature: %.3f C\n", (double)avg_temperature);

        printk("====================================\n");

        /* 6. Save averaged temperature */
        save_temp_to_memory(
            active_rtds[i].action_id,
            (int16_t)(avg_temperature * 10.0f)
        );
    }

#endif

// #else
//     /* --- HARDWARE CODE --- */
//     int err;
//     int32_t adc_val1 = 0;
//     int32_t adc_val2 = 0;
//     /* Read all 11 RTDs sequentially */

    
//     for (int i = 0; i < num_active_rtds; i++) 
//     {
//         k_msleep(500);
//         /* 1. Select the sensor via the external MUX */
//         set_rtd_mux_channel(active_rtds[i].mux_channel);
//         /* 2. Settle time for MUX switch and analog filter (e.g. 1 ms) */
//         k_msleep(500);
//         /* 3. Setup ADS124S08: IDAC1 stays on AIN11, sense on active input_positive */
//         struct adc_channel_cfg cfg = {
//             .channel_id = 0,
//             .differential = true,
//             .input_positive = active_rtds[i].input_positive,
//             .input_negative = active_rtds[i].input_negative,
//             .gain = ADC_GAIN_1,
//             .reference = ADC_REF_EXTERNAL0,
//             .acquisition_time = ADC_ACQ_TIME_DEFAULT,
//             .current_source_pin_set = true,
//             .current_source_pin = { 11, 15 } /* IDAC1 on AIN11, IDAC2 off */
//         };
             
        
        
//         err = adc_channel_setup(ads_dev, &cfg);
//         if (err != 0) 
//         {
//             LOG_ERR("ADC MUX setup failed for RTD%d: %d", i + 1, err);
//             continue;
//         }
        
//         /* Declare the sequence buffer for reading channel 0 */
//         struct adc_sequence sequence = {
//             .channels = BIT(0),
//             .buffer = &adc_val1,
//             .buffer_size = sizeof(adc_val1),
//             .resolution = 24,
//             .oversampling = 0,
//             .calibrate = false,
//         };
//         k_msleep(500);
        
//         /* 1st Read */
//         sequence.buffer = &adc_val1;

//         err = adc_read(ads_dev, &sequence);

//         if (err != 0) {
//             LOG_ERR("ADC Read 1 failed for RTD%d: %d", i + 1, err);
//             continue;
//         }

//         float r1 = adc_to_resistance(adc_val1);
//         float t1 = resistance_to_temperature(r1);
//         k_msleep(500);
//         /* 2nd Read */
//         sequence.buffer = &adc_val2;
//         err = adc_read(ads_dev, &sequence);
//         if (err == 0) 
//         {
//             float r2 = adc_to_resistance(adc_val2);
//             float t2 = resistance_to_temperature(r2);
//             save_temp_to_memory(active_rtds[i].action_id, (int16_t)(t2 * 10.0f));
//             /* Print 1st Read then 2nd Read */
//                         /* Print 1st Read then 2nd Read with Code in Decimal */
//             printk("\x1b[1;0uRTD%02d (AIN%d) [Read 1]: Code=%ld | R=%.2f Ohm | Temp=%.2f C\n",
//                 i + 1, active_rtds[i].input_positive,
//                 (long)adc_val1, (double)r1, (double)t1);

//             printk("RTD%02d (AIN%d) [Read 2]: Code=%ld | R=%.2f Ohm | Temp=%.2f C\n\x1b[0;0u",
//                 i + 1, active_rtds[i].input_positive,
//                 (long)adc_val2, (double)r2, (double)t2);
//         }
        
//         // /* 1st Read: Dummy read to flush digital filter and discard */
//         // adc_read(ads_dev, &sequence);
//         // /* 2nd Read: Valid, fully settled reading to keep */
//         // err = adc_read(ads_dev, &sequence);
//         // if (err == 0) 
//         // {
//         //     float resistance = adc_to_resistance(adc_value);
//         //     float temperature = resistance_to_temperature(resistance);
            
//         //     /* Scale float (20.5 C) to protocol int16_t (205) */
//         //     int16_t temp_scaled = (int16_t)(temperature * 10.0f);
            
//         //     /* Save to memory using its SENSOR_RTD_TEMP ID */
//         //     save_temp_to_memory(active_rtds[i].action_id, temp_scaled);
            
//         //     // printk("RTD%02d (AIN%d): Code=0x%06X | R=%.2f Ohm | Temp=%.2f C\n",  i + 1, active_rtds[i].input_positive,(uint32_t)(adc_value & 0x00FFFFFF),
//         //     //         (double)resistance, (double)temperature);

//         //     /* \x1b[1;0u switches to Terminal 1, \x1b[0;0u switches back to Terminal 0 */
//         //     printk("\x1b[1;0uRTD%02d (AIN%d): Code=0x%06X | R=%.2f Ohm | Temp=%.2f C\n\x1b[0;0u",
//         //         i + 1, active_rtds[i].input_positive,
//         //         (uint32_t)(adc_value & 0x00FFFFFF),
//         //         (double)resistance, (double)temperature);
//         // } 
//         // else 
//         // {
//         //     LOG_ERR("ADC read failed on RTD%d: %d", i + 1, err);
//         // }
//     }
// #endif
}
```

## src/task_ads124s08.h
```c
#ifndef TASK_ADS_H_
#define TASK_ADS_H_

/**
 * @brief Initialize the ADS124S08 peripheral and driver.
 * @return 0 on success, negative error code on failure.
 */
int ads_task_init(void);

/**
 * @brief Main handler for the ADS124S08 task.
 * Reads ADC values and updates the global state.
 */
void ads_task_run(void);

/**
 * @brief Thread-safe getter to retrieve the latest ADC/RTD value.
 * @return The current 24-bit processed value.
 */
float get_ads_rtd_value(void);

#endif /* TASK_ADS_H_H */
```

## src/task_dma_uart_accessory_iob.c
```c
#include <zephyr/kernel.h>
#include <zephyr/drivers/uart.h>
#include <zephyr/logging/log.h>
#include <zephyr/cache.h>
#include <zephyr/app_memory/app_memdomain.h>
#include <string.h>
#include "communication/framer.h"
#include "communication/parser.h"

LOG_MODULE_REGISTER(dma_uart_accessory_iob, LOG_LEVEL_DBG);

/* Devicetree node configuration for the target UART peripheral */
#define UART_DMA_NODE DT_NODELABEL(uart4) 
static const struct device *const uart_dev = DEVICE_DT_GET(UART_DMA_NODE);

static uint8_t accessory_iob_tx_buffer[128] __nocache;
static atomic_t tx_busy = ATOMIC_INIT(0);

/* RX Configuration: Double-buffering prevents data loss during processing */
#define RX_BUF_SIZE 64
static uint8_t rx_buf_1[RX_BUF_SIZE] __aligned(32) __nocache;
static uint8_t rx_buf_2[RX_BUF_SIZE] __aligned(32) __nocache;

static uint8_t *next_rx_buf = rx_buf_2;
static bool rx_active = false;

/* Queue to pass received chunks from ISR context to thread context */
struct rx_chunk_msg {
    uint8_t data[RX_BUF_SIZE];
    size_t len;
};
K_MSGQ_DEFINE(accessory_rx_msgq, sizeof(struct rx_chunk_msg), 10, 4);

/* The global framer instance */
static fd_framer_t framer;

/* Callback triggered by the framer when a valid packet is assembled */
static void on_valid_packet_received(const fd_packet_t *pkt)
{
    LOG_DBG("Valid packet framed. Routing to parser...");
    fd_parser_process_packet(INTERFACE_ACCESSORY_IOB, pkt);
}

/* Async UART Callback to catch DMA events */
static void dma_accessory_iob_callback(const struct device *dev, struct uart_event *evt, void *user_data)
{
    int ret;
    switch (evt->type) {
    case UART_TX_DONE:
        LOG_INF("Accessory IOB DMA transaction finished. Transmitted %zu bytes.", evt->data.tx.len);
        atomic_clear(&tx_busy);
        break;

    case UART_TX_ABORTED:
        LOG_ERR("Accessory IOB DMA transaction aborted!");
        atomic_clear(&tx_busy);
        break;

    /* --- RX Event Handling --- */
    case UART_RX_RDY:
        /* Fired when data is received or an idle timeout occurs */
        LOG_DBG("RX Data Ready: Received %zu bytes at offset %zu", 
                evt->data.rx.len, evt->data.rx.offset);
        
        if (evt->data.rx.len > 0) {
            struct rx_chunk_msg msg;
            msg.len = evt->data.rx.len;
            
            /* Prevent buffer overflow in case of unexpected length */
            if (msg.len > sizeof(msg.data)) {
                msg.len = sizeof(msg.data);
            }

            /* Copy data out of the DMA buffer immediately */
            memcpy(msg.data, evt->data.rx.buf + evt->data.rx.offset, msg.len);

            /* Send the data chunk to the thread for processing (K_NO_WAIT is crucial in ISR) */
            if (k_msgq_put(&accessory_rx_msgq, &msg, K_NO_WAIT) != 0) {
                LOG_ERR("RX Message Queue is full! Dropping %zu bytes", msg.len);
            }
        }
        break;

    case UART_RX_BUF_REQUEST:
        rx_active = true;
        LOG_DBG("Requesting buffer: %p", next_rx_buf); 
        ret = uart_rx_buf_rsp(dev, next_rx_buf, RX_BUF_SIZE);
        if (ret < 0) {
            LOG_ERR("Failed to provide next RX buffer: %d", ret);
        } else {
            /* Safely toggle the pointer for the NEXT request event */
            next_rx_buf = (next_rx_buf == rx_buf_1) ? rx_buf_2 : rx_buf_1;
        }
        break;

    case UART_RX_BUF_RELEASED:
        /* Fired when the driver is completely done with a buffer chunk */
        LOG_DBG("Buffer %p released by DMA engine.", (void *)evt->data.rx_buf.buf);
        break;

    case UART_RX_DISABLED:
        LOG_INF("UART RX disabled. Re-arming...");
        next_rx_buf = rx_buf_2; // Reset buffer pointer
        uart_rx_enable(dev, rx_buf_1, RX_BUF_SIZE, 5000);
        break;

    case UART_RX_STOPPED:
        rx_active = false;
        LOG_WRN("RX Stopped: %d", evt->data.rx_stop.reason);
        break;

    default:
        break;
    }
}

/* Initialization Function */
int dma_uart_accessory_iob_init(void)
{
    /* 1. Initialize our protocol framer state machine */
    fd_framer_init(&framer, on_valid_packet_received);

    /* 2. Force the peripheral to a clean state */
    uart_irq_rx_disable(uart_dev);
    uart_irq_tx_disable(uart_dev);

    if (!device_is_ready(uart_dev)) {
        LOG_ERR("Display UART hardware not ready");
        return -1;
    }

    int ret = uart_callback_set(uart_dev, dma_accessory_iob_callback, NULL);
    if (ret < 0) {
        LOG_ERR("Failed to set Asynchronous UART Callback: %d", ret);
        return ret;
    }
    
    ret = uart_rx_enable(uart_dev, rx_buf_1, RX_BUF_SIZE, 5000);
    if (ret < 0) {
        LOG_ERR("Failed to start RX DMA: %d", ret);
    } else {
        LOG_INF("RX DMA started successfully.");
    }

    LOG_INF("DMA UART Accessory IOB context fully initialized (TX & RX).");

    /* TEST MESSAGE: Send a dummy read request to RealTerm */
    /* 4C 43 03 01 04 02 0A 00 */
    uint8_t test_msg[] = {0x4C, 0x43, 0x03, 0x01, 0x04, 0x02, 0x0A, 0x00};
    
    /* Forward declaration so the compiler knows about the function below */
    extern void fd_protocol_send_accessory_iob_dma(const uint8_t *data, size_t len);
    
    fd_protocol_send_accessory_iob_dma(test_msg, sizeof(test_msg));

    return 0;
}

/* Runner / Handler Function */
void dma_uart_accessory_iob_run(void)
{
    struct rx_chunk_msg msg;

    /* Block until new DMA bytes arrive in the queue */
    if (k_msgq_get(&accessory_rx_msgq, &msg, K_FOREVER) == 0) {
        
        /* 
         * Feed bytes into the framer state machine.
         * If a complete frame is formed, the framer will synchronously 
         * fire the `on_valid_packet_received` callback on this thread context.
         */
        fd_framer_feed_bytes(&framer, msg.data, msg.len);
    }

    
}

/* Function to transmit a protocol frame over UART DMA */
void fd_protocol_send_accessory_iob_dma(const uint8_t *data, size_t len)
{
    /* Wait if a transmission is already in progress */
    if (atomic_get(&tx_busy) != 0) {
        LOG_WRN("TX busy, dropping packet!");
        return;
    }

    /* Ensure we don't overflow our TX buffer */
    if (len > sizeof(accessory_iob_tx_buffer)) {
        LOG_ERR("Frame too large for TX buffer!");
        return;
    }

    /* Copy to the non-cached DMA buffer */
    memcpy(accessory_iob_tx_buffer, data, len);
    
    /* Flush D-cache to physical RAM before triggering DMA (required for Zephyr on STM32F7) */
    sys_cache_data_flush_range(accessory_iob_tx_buffer, len);

    atomic_set(&tx_busy, 1);

    int ret = uart_tx(uart_dev, accessory_iob_tx_buffer, len, SYS_FOREVER_US);
    if (ret < 0) {
        LOG_ERR("Failed to initiate DMA TX: %d", ret);
        atomic_clear(&tx_busy);
    }
}
```
